VERSION 5.7 ;
  NOWIREEXTENSIONATPIN ON ;
  DIVIDERCHAR "/" ;
  BUSBITCHARS "[]" ;
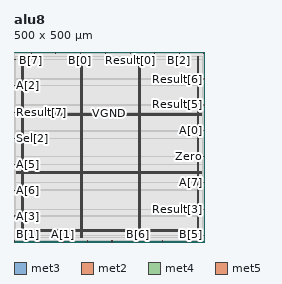
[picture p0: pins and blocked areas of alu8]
MACRO alu8
  CLASS BLOCK ;
  FOREIGN alu8 ;
  ORIGIN 0.000 0.000 ;
  SIZE 500.000 BY 500.000 ;
  PIN A[0]
    DIRECTION INPUT ;
    USE SIGNAL ;
    ANTENNAGATEAREA 0.247500 ;
    PORT
      LAYER met3 ;
        RECT 496.000 292.440 500.000 293.040 ;
    END
  END A[0]
  PIN A[1]
    DIRECTION INPUT ;
    USE SIGNAL ;
    ANTENNAGATEAREA 0.159000 ;
    PORT
      LAYER met2 ;
        RECT 128.890 0.000 129.170 4.000 ;
    END
  END A[1]
  PIN A[2]
    DIRECTION INPUT ;
    USE SIGNAL ;
    ANTENNAGATEAREA 0.247500 ;
    PORT
      LAYER met3 ;
        RECT 0.000 411.440 4.000 412.040 ;
    END
  END A[2]
  PIN A[3]
    DIRECTION INPUT ;
    USE SIGNAL ;
    ANTENNAGATEAREA 0.426000 ;
    PORT
      LAYER met3 ;
        RECT 0.000 68.040 4.000 68.640 ;
    END
  END A[3]
  PIN A[4]
    DIRECTION INPUT ;
    USE SIGNAL ;
    ANTENNAGATEAREA 0.159000 ;
    PORT
      LAYER met2 ;
        RECT 389.710 0.000 389.990 4.000 ;
    END
  END A[4]
  PIN A[5]
    DIRECTION INPUT ;
    USE SIGNAL ;
    ANTENNAGATEAREA 0.213000 ;
    PORT
      LAYER met3 ;
        RECT 0.000 204.040 4.000 204.640 ;
    END
  END A[5]
  PIN A[6]
    DIRECTION INPUT ;
    USE SIGNAL ;
    ANTENNAGATEAREA 0.247500 ;
    PORT
      LAYER met3 ;
        RECT 0.000 136.040 4.000 136.640 ;
    END
  END A[6]
  PIN A[7]
    DIRECTION INPUT ;
    USE SIGNAL ;
    ANTENNAGATEAREA 0.247500 ;
    PORT
      LAYER met3 ;
        RECT 496.000 156.440 500.000 157.040 ;
    END
  END A[7]
  PIN B[0]
    DIRECTION INPUT ;
    USE SIGNAL ;
    ANTENNAGATEAREA 0.159000 ;
    PORT
      LAYER met2 ;
        RECT 173.970 496.000 174.250 500.000 ;
    END
  END B[0]
  PIN B[1]
    DIRECTION INPUT ;
    USE SIGNAL ;
    ANTENNAGATEAREA 0.247500 ;
    PORT
      LAYER met2 ;
        RECT 0.090 0.000 0.370 4.000 ;
    END
  END B[1]
  PIN B[2]
    DIRECTION INPUT ;
    USE SIGNAL ;
    ANTENNAGATEAREA 0.247500 ;
    PORT
      LAYER met2 ;
        RECT 434.790 496.000 435.070 500.000 ;
    END
  END B[2]
  PIN B[3]
    DIRECTION INPUT ;
    USE SIGNAL ;
    ANTENNAGATEAREA 0.426000 ;
    PORT
      LAYER met2 ;
        RECT 499.190 496.000 499.470 500.000 ;
    END
  END B[3]
  PIN B[4]
    DIRECTION INPUT ;
    USE SIGNAL ;
    ANTENNAGATEAREA 0.213000 ;
    PORT
      LAYER met2 ;
        RECT 370.390 496.000 370.670 500.000 ;
    END
  END B[4]
  PIN B[5]
    DIRECTION INPUT ;
    USE SIGNAL ;
    ANTENNAGATEAREA 0.213000 ;
    PORT
      LAYER met3 ;
        RECT 496.000 17.040 500.000 17.640 ;
    END
  END B[5]
  PIN B[6]
    DIRECTION INPUT ;
    USE SIGNAL ;
    ANTENNAGATEAREA 0.159000 ;
    PORT
      LAYER met2 ;
        RECT 325.310 0.000 325.590 4.000 ;
    END
  END B[6]
  PIN B[7]
    DIRECTION INPUT ;
    USE SIGNAL ;
    ANTENNAGATEAREA 0.247500 ;
    PORT
      LAYER met2 ;
        RECT 45.170 496.000 45.450 500.000 ;
    END
  END B[7]
  PIN CarryOut
    DIRECTION OUTPUT TRISTATE ;
    USE SIGNAL ;
    ANTENNADIFFAREA 0.795200 ;
    PORT
      LAYER met2 ;
        RECT 454.110 0.000 454.390 4.000 ;
    END
  END CarryOut
  PIN Result[0]
    DIRECTION OUTPUT TRISTATE ;
    USE SIGNAL ;
    ANTENNADIFFAREA 0.795200 ;
    PORT
      LAYER met2 ;
        RECT 305.990 496.000 306.270 500.000 ;
    END
  END Result[0]
  PIN Result[1]
    DIRECTION OUTPUT TRISTATE ;
    USE SIGNAL ;
    ANTENNADIFFAREA 0.795200 ;
    PORT
      LAYER met2 ;
        RECT 64.490 0.000 64.770 4.000 ;
    END
  END Result[1]
  PIN Result[2]
    DIRECTION OUTPUT TRISTATE ;
    USE SIGNAL ;
    ANTENNADIFFAREA 0.795200 ;
    PORT
      LAYER met2 ;
        RECT 109.570 496.000 109.850 500.000 ;
    END
  END Result[2]
  PIN Result[3]
    DIRECTION OUTPUT TRISTATE ;
    USE SIGNAL ;
    ANTENNADIFFAREA 0.445500 ;
    PORT
      LAYER met3 ;
        RECT 496.000 85.040 500.000 85.640 ;
    END
  END Result[3]
  PIN Result[4]
    DIRECTION OUTPUT TRISTATE ;
    USE SIGNAL ;
    ANTENNADIFFAREA 0.795200 ;
    PORT
      LAYER met2 ;
        RECT 193.290 0.000 193.570 4.000 ;
    END
  END Result[4]
  PIN Result[5]
    DIRECTION OUTPUT TRISTATE ;
    USE SIGNAL ;
    ANTENNADIFFAREA 0.445500 ;
    PORT
      LAYER met3 ;
        RECT 496.000 360.440 500.000 361.040 ;
    END
  END Result[5]
  PIN Result[6]
    DIRECTION OUTPUT TRISTATE ;
    USE SIGNAL ;
    ANTENNADIFFAREA 0.445500 ;
    PORT
      LAYER met3 ;
        RECT 496.000 428.440 500.000 429.040 ;
    END
  END Result[6]
  PIN Result[7]
    DIRECTION OUTPUT TRISTATE ;
    USE SIGNAL ;
    ANTENNADIFFAREA 0.795200 ;
    PORT
      LAYER met3 ;
        RECT 0.000 340.040 4.000 340.640 ;
    END
  END Result[7]
  PIN Sel[0]
    DIRECTION INPUT ;
    USE SIGNAL ;
    ANTENNAGATEAREA 0.213000 ;
    PORT
      LAYER met2 ;
        RECT 241.590 496.000 241.870 500.000 ;
    END
  END Sel[0]
  PIN Sel[1]
    DIRECTION INPUT ;
    USE SIGNAL ;
    ANTENNAGATEAREA 0.159000 ;
    PORT
      LAYER met2 ;
        RECT 257.690 0.000 257.970 4.000 ;
    END
  END Sel[1]
  PIN Sel[2]
    DIRECTION INPUT ;
    USE SIGNAL ;
    ANTENNAGATEAREA 0.213000 ;
    PORT
      LAYER met3 ;
        RECT 0.000 272.040 4.000 272.640 ;
    END
  END Sel[2]
  PIN Sel[3]
    DIRECTION INPUT ;
    USE SIGNAL ;
    ANTENNAGATEAREA 0.247500 ;
    PORT
      LAYER met3 ;
        RECT 0.000 479.440 4.000 480.040 ;
    END
  END Sel[3]
  PIN VGND
    DIRECTION INOUT ;
    USE GROUND ;
    PORT
      LAYER met4 ;
        RECT 24.340 10.640 25.940 487.120 ;
    END
    PORT
      LAYER met4 ;
        RECT 177.940 10.640 179.540 487.120 ;
    END
    PORT
      LAYER met4 ;
        RECT 331.540 10.640 333.140 487.120 ;
    END
    PORT
      LAYER met4 ;
        RECT 485.140 10.640 486.740 487.120 ;
    END
    PORT
      LAYER met5 ;
        RECT 5.280 30.030 494.280 31.630 ;
    END
    PORT
      LAYER met5 ;
        RECT 5.280 183.210 494.280 184.810 ;
    END
    PORT
      LAYER met5 ;
        RECT 5.280 336.390 494.280 337.990 ;
    END
  END VGND
  PIN VPWR
    DIRECTION INOUT ;
    USE POWER ;
    PORT
      LAYER met4 ;
        RECT 21.040 10.640 22.640 487.120 ;
    END
    PORT
      LAYER met4 ;
        RECT 174.640 10.640 176.240 487.120 ;
    END
    PORT
      LAYER met4 ;
        RECT 328.240 10.640 329.840 487.120 ;
    END
    PORT
      LAYER met4 ;
        RECT 481.840 10.640 483.440 487.120 ;
    END
    PORT
      LAYER met5 ;
        RECT 5.280 26.730 494.280 28.330 ;
    END
    PORT
      LAYER met5 ;
        RECT 5.280 179.910 494.280 181.510 ;
    END
    PORT
      LAYER met5 ;
        RECT 5.280 333.090 494.280 334.690 ;
    END
  END VPWR
  PIN Zero
    DIRECTION OUTPUT TRISTATE ;
    USE SIGNAL ;
    ANTENNADIFFAREA 1.336500 ;
    PORT
      LAYER met3 ;
        RECT 496.000 224.440 500.000 225.040 ;
    END
  END Zero
  OBS
      LAYER li1 ;
        RECT 5.520 10.795 494.040 486.965 ;
      LAYER met1 ;
        RECT 0.070 10.640 499.490 487.120 ;
      LAYER met2 ;
        RECT 0.100 495.720 44.890 496.810 ;
        RECT 45.730 495.720 109.290 496.810 ;
        RECT 110.130 495.720 173.690 496.810 ;
        RECT 174.530 495.720 241.310 496.810 ;
        RECT 242.150 495.720 305.710 496.810 ;
        RECT 306.550 495.720 370.110 496.810 ;
        RECT 370.950 495.720 434.510 496.810 ;
        RECT 435.350 495.720 498.910 496.810 ;
        RECT 0.100 4.280 499.460 495.720 ;
        RECT 0.650 4.000 64.210 4.280 ;
        RECT 65.050 4.000 128.610 4.280 ;
        RECT 129.450 4.000 193.010 4.280 ;
        RECT 193.850 4.000 257.410 4.280 ;
        RECT 258.250 4.000 325.030 4.280 ;
        RECT 325.870 4.000 389.430 4.280 ;
        RECT 390.270 4.000 453.830 4.280 ;
        RECT 454.670 4.000 499.460 4.280 ;
      LAYER met3 ;
        RECT 4.000 480.440 496.000 487.045 ;
        RECT 4.400 479.040 496.000 480.440 ;
        RECT 4.000 429.440 496.000 479.040 ;
        RECT 4.000 428.040 495.600 429.440 ;
        RECT 4.000 412.440 496.000 428.040 ;
        RECT 4.400 411.040 496.000 412.440 ;
        RECT 4.000 361.440 496.000 411.040 ;
        RECT 4.000 360.040 495.600 361.440 ;
        RECT 4.000 341.040 496.000 360.040 ;
        RECT 4.400 339.640 496.000 341.040 ;
        RECT 4.000 293.440 496.000 339.640 ;
        RECT 4.000 292.040 495.600 293.440 ;
        RECT 4.000 273.040 496.000 292.040 ;
        RECT 4.400 271.640 496.000 273.040 ;
        RECT 4.000 225.440 496.000 271.640 ;
        RECT 4.000 224.040 495.600 225.440 ;
        RECT 4.000 205.040 496.000 224.040 ;
        RECT 4.400 203.640 496.000 205.040 ;
        RECT 4.000 157.440 496.000 203.640 ;
        RECT 4.000 156.040 495.600 157.440 ;
        RECT 4.000 137.040 496.000 156.040 ;
        RECT 4.400 135.640 496.000 137.040 ;
        RECT 4.000 86.040 496.000 135.640 ;
        RECT 4.000 84.640 495.600 86.040 ;
        RECT 4.000 69.040 496.000 84.640 ;
        RECT 4.400 67.640 496.000 69.040 ;
        RECT 4.000 18.040 496.000 67.640 ;
        RECT 4.000 16.640 495.600 18.040 ;
        RECT 4.000 10.715 496.000 16.640 ;
  END
END alu8
END LIBRARY

